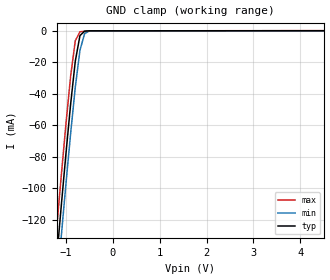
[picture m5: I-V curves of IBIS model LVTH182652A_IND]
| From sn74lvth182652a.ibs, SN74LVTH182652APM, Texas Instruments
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[Model]   LVTH182652A_IND
| input buffer with pulldown resistor
| indo.lvta (97212 ALEY)
| pad.lvta  (97212 ALEY)
| Signals   OE
Model_type  Input
Polarity   Non-Inverting
Vinl = 0.8V
Vinh = 2.0V
| variable   typ   min   max
C_comp   4p   NA   NA
[Temperature Range]   50   100   0
[Voltage range]   3.3   3   3.6
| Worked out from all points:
|   GND clamp passes 1 mA (typ) near -0.63 V on its own axis
|Process range|   weak   strong
[gnd_clamp]
|   50C:3.3V:   100C:3V:weak   0C:3.6V:strong
|   Voltage   I(typ)   I(min)   I(max)
-3.3V     -902.8mA   -920.5mA   -885.5mA
-1.2V     -145.7mA   -165.1mA   -126.6mA
-1.1V     -111.6mA   -131mA     -92.49mA
-1V       -78.36mA   -97.58mA   -59.49mA
-900mV    -46.84mA   -65.49mA   -29.02mA
-800mV    -19.33mA   -35.9mA    -6.338mA
-700mV    -3.029mA   -12.3mA    -615.1uA
-600mV    -185uA     -1.696mA   -241.1uA
-500mV    -12.66uA   -130.7uA   -61.31uA
6.6V      99.51uA    66.38uA    159.2uA
